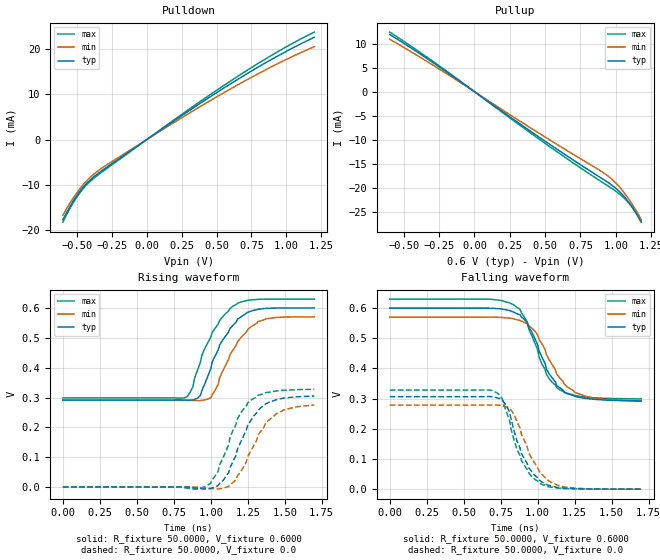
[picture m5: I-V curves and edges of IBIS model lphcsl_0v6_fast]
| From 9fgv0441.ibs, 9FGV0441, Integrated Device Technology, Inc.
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|   Model Clkout lphcsl_0v6_fast
[Model]  lphcsl_0v6_fast
Model_type Output
Polarity   Non-Inverting
Enable   Active-High
Vmeas =  0.4000V
Cref =   2.0000pF
Rref =   0.0
Vref =   0.4000V
C_comp   1.1000pF   1.0000pF   1.2000pF
[Temperature Range]   25.0000   75.0000   0.0
[Voltage Range]   0.6000V   0.5700V   0.6300V
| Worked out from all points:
|   slope of the pulldown table from 0 to 0.09 V, typ, clamps not added: 46.7 ohm
|   slope of the pullup table from 0 to 0.09 V, typ, clamps not added: 47.4 ohm
|   rising waveform, R_fixture 50.0000, V_fixture 0.6000: 20-80 % time 178ps typ, 179ps min, 178ps max; typ from 0.292 V to 0.6 V
|   rising waveform, R_fixture 50.0000, V_fixture 0.0: 20-80 % time 173ps typ, 176ps min, 168ps max; typ from 0 V to 0.305 V
|   falling waveform, R_fixture 50.0000, V_fixture 0.6000: 20-80 % time 182ps typ, 186ps min, 161ps max; typ from 0.6 V to 0.293 V
|   falling waveform, R_fixture 50.0000, V_fixture 0.0: 20-80 % time 140ps typ, 156ps min, 145ps max; typ from 0.306 V to 0 V
[Pulldown]
|Voltage   I(typ)   I(min)   I(max)
-600mV    -17.73mA   -16.75mA   -18.28mA
-540mV    -14.34mA   -13.62mA   -14.73mA
-480mV    -11.53mA   -10.95mA   -11.85mA
-440mV    -10.02mA   -9.465mA   -10.34mA
-400mV    -8.789mA   -8.218mA   -9.125mA
-320mV    -6.852mA   -6.295mA   -7.17mA
220mV     4.677mA    4.26mA     4.908mA
600mV     12.35mA    11.23mA    12.98mA
900mV     17.87mA    16.23mA    18.79mA
1.2V      22.67mA    20.58mA    23.82mA
[Pullup]
|Voltage   I(typ)   I(min)   I(max)
-600mV    11.94mA    10.94mA    12.43mA
-240mV    4.975mA    4.548mA    5.191mA
540mV     -11.13mA   -10.19mA   -11.61mA
940mV     -18.82mA   -17.47mA   -19.56mA
1V        -20.13mA   -19.02mA   -20.75mA
1.06V     -21.88mA   -21.09mA   -22.2mA
1.12V     -24.25mA   -23.65mA   -24.21mA
1.18V     -27.21mA   -26.66mA   -26.93mA
[Ramp]
| variable   typ   min   max
dV/dt_r  0.1828/0.1658n   0.1646/0.1750n   0.1965/0.1629n
dV/dt_f  0.1844/0.1738n   0.1666/0.1919n   0.1984/0.1620n
R_load = 50.0000
[Rising Waveform]
R_fixture= 50.0000
V_fixture= 0.6000
V_fixture_min= 0.5700
V_fixture_max= 0.6300
|time   V(typ)   V(min)   V(max)
0s        291.6mV    290.4mV    298.7mV
820ps     291.4mV    290.4mV    298.7mV
880ps     291.7mV    290.1mV    337.4mV
930ps     306.8mV    289.8mV    418.2mV
1ns       396.3mV    299.1mV    502.5mV
1.06ns    476mV      366.2mV    558.4mV
1.15ns    541.9mV    459.2mV    606.7mV
1.25ns    586mV      528.5mV    626.2mV
1.32ns    596mV      554.5mV    629.5mV
1.7ns     600.2mV    570.4mV    630.1mV
[Rising Waveform]
R_fixture= 50.0000
V_fixture= 0.0
V_fixture_min= 0.0
V_fixture_max= 0.0
|time   V(typ)   V(min)   V(max)
0s        0V         0V         0V
890ps     -3.58mV    -655.8uV   -7.526mV
1ns       -5.691mV   -4.788mV   12.59mV
1.05ns    4.772mV    -6.81mV    52.76mV
1.12ns    47.29mV    1.279mV    141.1mV
1.18ns    126.3mV    36.85mV    227.6mV
1.25ns    206.6mV    101.7mV    281.9mV
1.37ns    278.3mV    213.9mV    316.1mV
1.44ns    292.4mV    244.9mV    321.9mV
1.7ns     304.7mV    274.4mV    327.5mV
[Falling Waveform]
R_fixture= 50.0000
V_fixture= 0.6000
V_fixture_min= 0.5700
V_fixture_max= 0.6300
|time   V(typ)   V(min)   V(max)
0s        600mV      570mV      630mV
810ps     592.3mV    567mV      617.6mV
880ps     578.2mV    559.4mV    596.6mV
930ps     551.6mV    548.4mV    553.8mV
980ps     500.6mV    524.8mV    485.7mV
1.06ns    397.8mV    445.5mV    380.9mV
1.13ns    343.1mV    381.2mV    336.2mV
1.2ns     318mV      338.8mV    316.5mV
1.32ns    301.1mV    308.3mV    305.4mV
1.7ns     292.6mV    292.3mV    299.3mV
[Falling Waveform]
R_fixture= 50.0000
V_fixture= 0.0
V_fixture_min= 0.0
V_fixture_max= 0.0
|time   V(typ)   V(min)   V(max)
0s        306.5mV    278.5mV    328.5mV
690ps     306.6mV    278.8mV    327.3mV
760ps     296.2mV    277.1mV    300.6mV
810ps     256.1mV    268.7mV    227.7mV
820ps     233.2mV    262.8mV    199.6mV
890ps     118.8mV    182.7mV    95.62mV
1.01ns    30.83mV    59.83mV    20.86mV
1.06ns    15.44mV    32.63mV    10.17mV
1.18ns    3.389mV    7.484mV    2.238mV
1.7ns     139.5uV    252uV      103.6uV
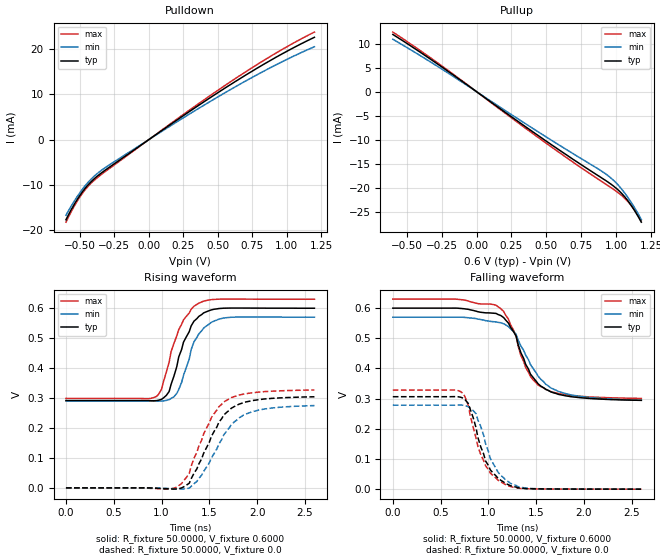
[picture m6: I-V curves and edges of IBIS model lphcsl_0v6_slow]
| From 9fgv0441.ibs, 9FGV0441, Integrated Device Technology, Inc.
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|   Model lphcsl_0v6_slow
[Model]  lphcsl_0v6_slow
Model_type Output
Polarity   Non-Inverting
Enable   Active-High
Vmeas =  0.4000V
Cref =   2.0000pF
Rref =   0.0
Vref =   0.4000V
C_comp   1.1000pF   1.0000pF   1.2000pF
[Temperature Range]   25.0000   75.0000   0.0
[Voltage Range]   0.6000V   0.5700V   0.6300V
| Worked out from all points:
|   slope of the pulldown table from 0 to 0.09 V, typ, clamps not added: 46.7 ohm
|   slope of the pullup table from 0 to 0.09 V, typ, clamps not added: 47.4 ohm
|   rising waveform, R_fixture 50.0000, V_fixture 0.6000: 20-80 % time 199ps typ, 187ps min, 207ps max; typ from 0.292 V to 0.6 V
|   rising waveform, R_fixture 50.0000, V_fixture 0.0: 20-80 % time 287ps typ, 320ps min, 278ps max; typ from 0 V to 0.304 V
|   falling waveform, R_fixture 50.0000, V_fixture 0.6000: 20-80 % time 277ps typ, 310ps min, 249ps max; typ from 0.6 V to 0.294 V
|   falling waveform, R_fixture 50.0000, V_fixture 0.0: 20-80 % time 196ps typ, 203ps min, 199ps max; typ from 0.306 V to 0 V
[Pulldown]
|Voltage   I(typ)   I(min)   I(max)
-600mV    -17.73mA   -16.75mA   -18.28mA
-540mV    -14.34mA   -13.62mA   -14.73mA
-480mV    -11.53mA   -10.95mA   -11.85mA
-440mV    -10.02mA   -9.465mA   -10.34mA
-400mV    -8.789mA   -8.218mA   -9.125mA
-320mV    -6.852mA   -6.295mA   -7.17mA
220mV     4.677mA    4.26mA     4.908mA
600mV     12.35mA    11.23mA    12.98mA
900mV     17.87mA    16.23mA    18.79mA
1.2V      22.67mA    20.58mA    23.82mA
[Pullup]
|Voltage   I(typ)   I(min)   I(max)
-600mV    11.94mA    10.94mA    12.43mA
-240mV    4.975mA    4.548mA    5.191mA
540mV     -11.13mA   -10.19mA   -11.61mA
940mV     -18.82mA   -17.47mA   -19.56mA
1V        -20.13mA   -19.02mA   -20.75mA
1.06V     -21.88mA   -21.09mA   -22.2mA
1.12V     -24.25mA   -23.65mA   -24.21mA
1.18V     -27.21mA   -26.66mA   -26.93mA
[Ramp]
| variable   typ   min   max
dV/dt_r  0.1826/0.2924n   0.1649/0.3119n   0.1961/0.2863n
dV/dt_f  0.1834/0.2952n   0.1651/0.3356n   0.1975/0.2766n
R_load = 50.0000
[Rising Waveform]
R_fixture= 50.0000
V_fixture= 0.6000
V_fixture_min= 0.5700
V_fixture_max= 0.6300
|time   V(typ)   V(min)   V(max)
0s        291.6mV    290.4mV    298.7mV
950ps     291.5mV    290mV      306.1mV
1ns       295.8mV    289.9mV    329.4mV
1.08ns    322.2mV    294.9mV    420.6mV
1.16ns    405.4mV    315.9mV    508.1mV
1.23ns    486.8mV    376mV      561.2mV
1.31ns    541mV      461.9mV    596.7mV
1.44ns    584.4mV    533.5mV    623.7mV
1.68ns    600.4mV    568.5mV    630.7mV
2.6ns     600.1mV    570.2mV    630.1mV
[Rising Waveform]
R_fixture= 50.0000
V_fixture= 0.0
V_fixture_min= 0.0
V_fixture_max= 0.0
|time   V(typ)   V(min)   V(max)
0s        0V         0V         0V
1.16ns    -3.564mV   -2.85mV    2.387mV
1.29ns    15.53mV    -1.023mV   47.73mV
1.34ns    48.97mV    13.95mV    99.71mV
1.37ns    63.74mV    21.58mV    119mV
1.52ns    170.6mV    99.09mV    233.8mV
1.65ns    243mV      176.5mV    286.9mV
1.81ns    279.5mV    233.7mV    310mV
1.94ns    291.2mV    253.8mV    317.4mV
2.6ns     304.3mV    274.9mV    326.9mV
[Falling Waveform]
R_fixture= 50.0000
V_fixture= 0.6000
V_fixture_min= 0.5700
V_fixture_max= 0.6300
|time   V(typ)   V(min)   V(max)
0s        600mV      570mV      630mV
1.08ns    582.5mV    554.3mV    609.7mV
1.16ns    568.6mV    548.2mV    589mV
1.29ns    507.2mV    513.2mV    507.8mV
1.34ns    451.9mV    474.6mV    442.6mV
1.39ns    413.8mV    444.1mV    403.1mV
1.52ns    349.3mV    374.6mV    345.2mV
1.65ns    323mV      336.1mV    323.8mV
1.86ns    306.7mV    312.7mV    310.9mV
2.6ns     294.4mV    294.9mV    300.8mV
[Falling Waveform]
R_fixture= 50.0000
V_fixture= 0.0
V_fixture_min= 0.0
V_fixture_max= 0.0
|time   V(typ)   V(min)   V(max)
0s        306.5mV    278.5mV    328.5mV
740ps     301.4mV    278.3mV    316.4mV
790ps     283.8mV    273.5mV    277.5mV
870ps     204.4mV    250.2mV    169.9mV
970ps     93.57mV    151.3mV    78.02mV
1.02ns    63.97mV    102.1mV    53.95mV
1.1ns     36.32mV    56.87mV    29.84mV
1.21ns    14.87mV    24.69mV    11.18mV
1.44ns    1.542mV    2.554mV    1.221mV
2.6ns     153.2uV    211.3uV    128.1uV
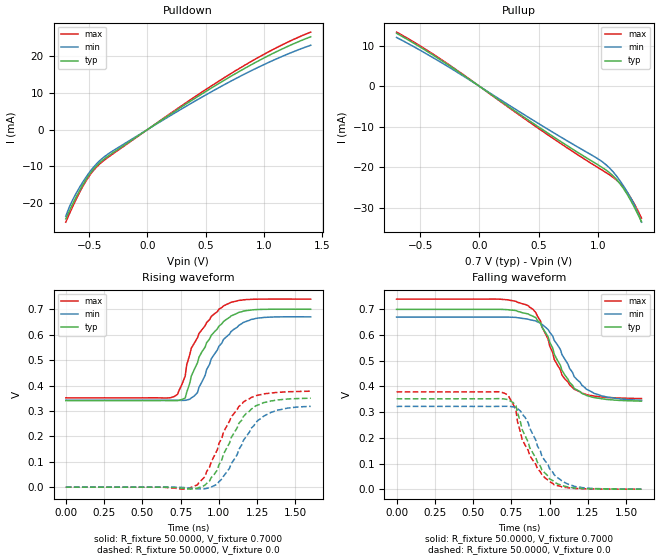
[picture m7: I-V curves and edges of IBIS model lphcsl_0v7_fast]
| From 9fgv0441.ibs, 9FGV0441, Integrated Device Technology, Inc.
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|   Model lphcsl_0v7_fast
[Model]  lphcsl_0v7_fast
Model_type Output
Polarity   Non-Inverting
Enable   Active-High
Vmeas =  0.4000V
Cref =   2.0000pF
Rref =   0.0
Vref =   0.4000V
C_comp   1.1000pF   1.0000pF   1.2000pF
[Temperature Range]   25.0000   75.0000   0.0
[Voltage Range]   0.7000V   0.6700V   0.7400V
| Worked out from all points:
|   slope of the pulldown table from 0 to 0.105 V, typ, clamps not added: 46.7 ohm
|   slope of the pullup table from 0 to 0.105 V, typ, clamps not added: 48.9 ohm
|   rising waveform, R_fixture 50.0000, V_fixture 0.7000: 20-80 % time 184ps typ, 189ps min, 167ps max; typ from 0.341 V to 0.7 V
|   rising waveform, R_fixture 50.0000, V_fixture 0.0: 20-80 % time 172ps typ, 185ps min, 179ps max; typ from 0 V to 0.35 V
|   falling waveform, R_fixture 50.0000, V_fixture 0.7000: 20-80 % time 180ps typ, 197ps min, 166ps max; typ from 0.7 V to 0.343 V
|   falling waveform, R_fixture 50.0000, V_fixture 0.0: 20-80 % time 157ps typ, 161ps min, 146ps max; typ from 0.352 V to 0 V
[Pulldown]
|Voltage   I(typ)   I(min)   I(max)
-700mV    -24.35mA   -23.64mA   -25.28mA
-670mV    -22.26mA   -21.16mA   -23.07mA
-640mV    -20.25mA   -19.13mA   -20.95mA
-580mV    -16.55mA   -15.66mA   -17.03mA
-520mV    -13.34mA   -12.68mA   -13.69mA
-430mV    -9.691mA   -9.131mA   -10.02mA
-340mV    -7.298mA   -6.726mA   -7.628mA
230mV     4.886mA    4.45mA     5.127mA
680mV     13.88mA    12.62mA    14.59mA
1.04V     20.22mA    18.36mA    21.25mA
1.22V     22.96mA    20.85mA    24.13mA
1.4V      25.34mA    23.03mA    26.62mA
[Pullup]
|Voltage   I(typ)   I(min)   I(max)
-700mV    13.05mA    12.03mA    13.35mA
-490mV    9.468mA    8.696mA    9.752mA
-310mV    6.146mA    5.633mA    6.355mA
500mV     -10.03mA   -9.194mA   -10.4mA
800mV     -15.73mA   -14.45mA   -16.3mA
1.04V     -20.06mA   -18.64mA   -20.72mA
1.13V     -22.08mA   -21.08mA   -22.44mA
1.22V     -25.3mA    -24.66mA   -24.97mA
1.25V     -26.68mA   -26.08mA   -26.14mA
1.31V     -29.84mA   -29.28mA   -29.02mA
1.34V     -31.57mA   -31.17mA   -30.68mA
1.37V     -33.4mA    -33.5mA    -32.47mA
[Ramp]
| variable   typ   min   max
dV/dt_r  0.2101/0.1771n   0.1909/0.1879n   0.2266/0.1755n
dV/dt_f  0.2143/0.1763n   0.1943/0.1928n   0.2323/0.1650n
R_load = 50.0000
[Rising Waveform]
R_fixture= 50.0000
V_fixture= 0.7000
V_fixture_min= 0.6700
V_fixture_max= 0.7400
|time   V(typ)   V(min)   V(max)
0s        340.9mV    342mV      351.5mV
710ps     340.3mV    342mV      357.1mV
780ps     350.7mV    341.7mV    436.8mV
790ps     373.5mV    343.1mV    481.7mV
820ps     437.2mV    351.1mV    546.8mV
860ps     489mV      371.9mV    587.6mV
950ps     597.2mV    505.1mV    671.9mV
1.03ns    651.8mV    581.1mV    713.2mV
1.21ns    697.1mV    659.9mV    739.1mV
1.6ns     700.1mV    670.3mV    740.1mV
[Rising Waveform]
R_fixture= 50.0000
V_fixture= 0.0
V_fixture_min= 0.0
V_fixture_max= 0.0
|time   V(typ)   V(min)   V(max)
0s        0V         0V         0V
810ps     -7.521mV   -3.728mV   -3.151mV
910ps     8.285mV    -6.321mV   42.33mV
990ps     67.83mV    11.68mV    147.1mV
1.03ns    130.4mV    42.94mV    216.4mV
1.08ns    194.2mV    91.72mV    275.7mV
1.16ns    277.7mV    184mV      335mV
1.24ns    320mV      253.8mV    360.2mV
1.31ns    334.7mV    285mV      368.4mV
1.6ns     350.1mV    318.1mV    377.6mV
[Falling Waveform]
R_fixture= 50.0000
V_fixture= 0.7000
V_fixture_min= 0.6700
V_fixture_max= 0.7400
|time   V(typ)   V(min)   V(max)
0s        700mV      670mV      740mV
680ps     700mV      670.1mV    739.5mV
840ps     684.7mV    663.5mV    719.1mV
910ps     667.5mV    654.9mV    687.2mV
990ps     593.6mV    621.5mV    584.4mV
1.03ns    525.9mV    579.3mV    505.2mV
1.08ns    463.2mV    524.7mV    445mV
1.16ns    392.3mV    438.1mV    389.5mV
1.29ns    356.6mV    373mV      362.4mV
1.6ns     342.9mV    346.1mV    352.9mV
[Falling Waveform]
R_fixture= 50.0000
V_fixture= 0.0
V_fixture_min= 0.0
V_fixture_max= 0.0
|time   V(typ)   V(min)   V(max)
0s        351.9mV    322.2mV    378.7mV
710ps     350.9mV    322.7mV    372.3mV
780ps     325.6mV    318.9mV    307.6mV
790ps     297.8mV    313.5mV    262.9mV
820ps     232.9mV    292.8mV    194.6mV
840ps     207.9mV    279.3mV    171.4mV
920ps     104.8mV    168.4mV    80.17mV
1ns       40.1mV     79.05mV    29.21mV
1.16ns    4.805mV    11.18mV    3.196mV
1.6ns     236.9uV    414.6uV    176.6uV
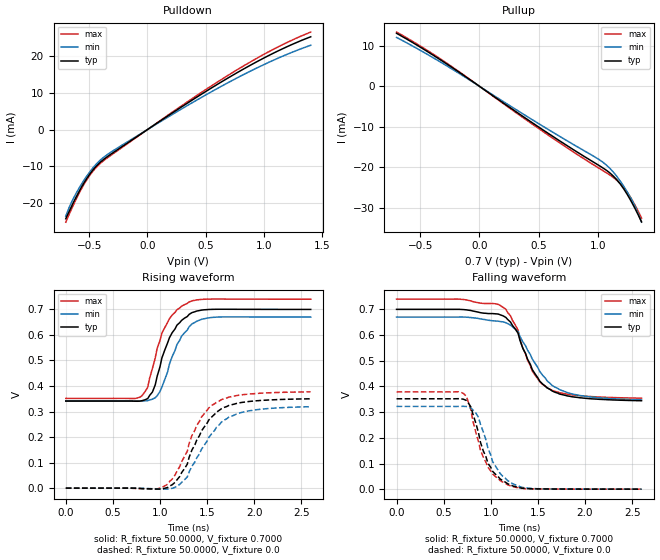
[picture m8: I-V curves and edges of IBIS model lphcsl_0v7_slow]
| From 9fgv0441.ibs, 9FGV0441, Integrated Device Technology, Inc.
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|   Model lphcsl_0v7_slow
[Model]  lphcsl_0v7_slow
Model_type Output
Polarity   Non-Inverting
Enable   Active-High
Vmeas =  0.4000V
Cref =   2.0000pF
Rref =   0.0
Vref =   0.4000V
C_comp   1.1000pF   1.0000pF   1.2000pF
[Temperature Range]   25.0000   75.0000   0.0
[Voltage Range]   0.7000V   0.6700V   0.7400V
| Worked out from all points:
|   slope of the pulldown table from 0 to 0.105 V, typ, clamps not added: 46.7 ohm
|   slope of the pullup table from 0 to 0.105 V, typ, clamps not added: 48.9 ohm
|   rising waveform, R_fixture 50.0000, V_fixture 0.7000: 20-80 % time 211ps typ, 219ps min, 209ps max; typ from 0.341 V to 0.7 V
|   rising waveform, R_fixture 50.0000, V_fixture 0.0: 20-80 % time 305ps typ, 334ps min, 298ps max; typ from 0 V to 0.35 V
|   falling waveform, R_fixture 50.0000, V_fixture 0.7000: 20-80 % time 285ps typ, 331ps min, 271ps max; typ from 0.7 V to 0.344 V
|   falling waveform, R_fixture 50.0000, V_fixture 0.0: 20-80 % time 198ps typ, 207ps min, 198ps max; typ from 0.352 V to 0 V
[Pulldown]
|Voltage   I(typ)   I(min)   I(max)
-700mV    -24.35mA   -23.64mA   -25.28mA
-670mV    -22.26mA   -21.16mA   -23.07mA
-640mV    -20.25mA   -19.13mA   -20.95mA
-580mV    -16.55mA   -15.66mA   -17.03mA
-520mV    -13.34mA   -12.68mA   -13.69mA
-430mV    -9.691mA   -9.131mA   -10.02mA
-340mV    -7.298mA   -6.726mA   -7.628mA
230mV     4.886mA    4.45mA     5.127mA
680mV     13.88mA    12.62mA    14.59mA
1.04V     20.22mA    18.36mA    21.25mA
1.22V     22.96mA    20.85mA    24.13mA
1.4V      25.34mA    23.03mA    26.62mA
[Pullup]
|Voltage   I(typ)   I(min)   I(max)
-700mV    13.05mA    12.03mA    13.35mA
-490mV    9.468mA    8.696mA    9.752mA
-310mV    6.146mA    5.633mA    6.355mA
500mV     -10.03mA   -9.194mA   -10.4mA
800mV     -15.73mA   -14.45mA   -16.3mA
1.04V     -20.06mA   -18.64mA   -20.72mA
1.13V     -22.08mA   -21.08mA   -22.44mA
1.22V     -25.3mA    -24.66mA   -24.97mA
1.25V     -26.68mA   -26.08mA   -26.14mA
1.31V     -29.84mA   -29.28mA   -29.02mA
1.34V     -31.57mA   -31.17mA   -30.68mA
1.37V     -33.4mA    -33.5mA    -32.47mA
[Ramp]
| variable   typ   min   max
dV/dt_r  0.2099/0.3249n   0.1913/0.3440n   0.2263/0.3187n
dV/dt_f  0.2134/0.3076n   0.1934/0.3467n   0.2314/0.2897n
R_load = 50.0000
[Rising Waveform]
R_fixture= 50.0000
V_fixture= 0.7000
V_fixture_min= 0.6700
V_fixture_max= 0.7400
|time   V(typ)   V(min)   V(max)
0s        340.9mV    342mV      351.5mV
790ps     340.9mV    341.6mV    356.5mV
870ps     350.8mV    342.8mV    395.1mV
920ps     376.5mV    348.5mV    469.3mV
1.02ns    509.7mV    395.5mV    607mV
1.1ns     589mV      485.4mV    663.5mV
1.18ns    638.4mV    562.8mV    698.5mV
1.31ns    680.9mV    632.5mV    729.3mV
1.55ns    700.2mV    668.6mV    740.6mV
2.6ns     700.1mV    670.1mV    740mV
[Rising Waveform]
R_fixture= 50.0000
V_fixture= 0.0
V_fixture_min= 0.0
V_fixture_max= 0.0
|time   V(typ)   V(min)   V(max)
0s        0V         0V         0V
1ns       -3.725mV   -2.933mV   -269.6uV
1.13ns    13.32mV    -760.9uV   35.8mV
1.29ns    94.06mV    44.03mV    144.8mV
1.34ns    150.1mV    86.22mV    207mV
1.44ns    223.7mV    151.8mV    278.4mV
1.6ns     297.4mV    238.6mV    336.3mV
1.73ns    323.7mV    277.7mV    356.2mV
1.89ns    336.7mV    298.6mV    366.5mV
2.6ns     349.9mV    318.9mV    377.2mV
[Falling Waveform]
R_fixture= 50.0000
V_fixture= 0.7000
V_fixture_min= 0.6700
V_fixture_max= 0.7400
|time   V(typ)   V(min)   V(max)
0s        700mV      670mV      740mV
660ps     700.1mV    670mV      740mV
1.08ns    681.7mV    654mV      719mV
1.16ns    668.7mV    648.1mV    700.4mV
1.29ns    606.7mV    613mV      618.6mV
1.34ns    549.2mV    573.8mV    549mV
1.44ns    466.1mV    507mV      460.6mV
1.6ns     394.2mV    421mV      394.1mV
1.94ns    356.1mV    365mV      364.1mV
2.6ns     344.4mV    347.6mV    354.3mV
[Falling Waveform]
R_fixture= 50.0000
V_fixture= 0.0
V_fixture_min= 0.0
V_fixture_max= 0.0
|time   V(typ)   V(min)   V(max)
0s        351.9mV    322.2mV    378.7mV
710ps     350.2mV    322.6mV    372.8mV
740ps     345.7mV    322mV      362.4mV
790ps     319.4mV    315.9mV    307.2mV
870ps     219.5mV    279.9mV    184.3mV
970ps     100.9mV    159.3mV    85.56mV
1.02ns    69.37mV    107.3mV    59.48mV
1.18ns    21.11mV    33.12mV    17.12mV
1.44ns    1.65mV     2.75mV     1.363mV
2.6ns     158uV      217uV      133.3uV
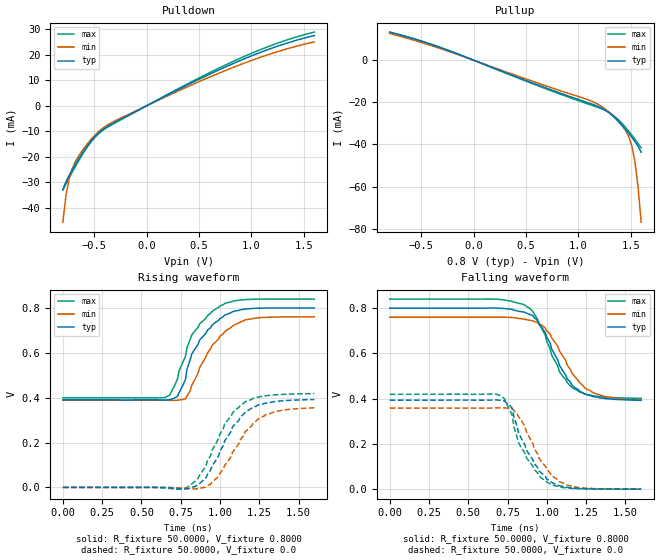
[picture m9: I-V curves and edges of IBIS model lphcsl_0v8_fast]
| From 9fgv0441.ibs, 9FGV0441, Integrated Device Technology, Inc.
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|   Model lphcsl_0v8_fast
[Model]  lphcsl_0v8_fast
Model_type Output
Polarity   Non-Inverting
Enable   Active-High
Vmeas =  0.4000V
Cref =   2.0000pF
Rref =   0.0
Vref =   0.4000V
C_comp   1.1000pF   1.0000pF   1.2000pF
[Temperature Range]   25.0000   75.0000   0.0
[Voltage Range]   0.8000V   0.7600V   0.8400V
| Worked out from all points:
|   slope of the pulldown table from 0 to 0.12 V, typ, clamps not added: 46.7 ohm
|   slope of the pullup table from 0 to 0.12 V, typ, clamps not added: 51 ohm
|   rising waveform, R_fixture 50.0000, V_fixture 0.8000: 20-80 % time 171ps typ, 195ps min, 176ps max; typ from 0.39 V to 0.8 V
|   rising waveform, R_fixture 50.0000, V_fixture 0.0: 20-80 % time 189ps typ, 199ps min, 184ps max; typ from 0 V to 0.392 V
|   falling waveform, R_fixture 50.0000, V_fixture 0.8000: 20-80 % time 185ps typ, 195ps min, 175ps max; typ from 0.8 V to 0.393 V
|   falling waveform, R_fixture 50.0000, V_fixture 0.0: 20-80 % time 160ps typ, 168ps min, 150ps max; typ from 0.394 V to 0 V
[Pulldown]
|Voltage   I(typ)   I(min)   I(max)
-800mV    -32.9mA    -45.7mA    -33.08mA
-770mV    -29.78mA   -35.16mA   -30.65mA
-740mV    -27.3mA    -28.65mA   -28.32mA
-710mV    -25.06mA   -24.65mA   -26.03mA
-650mV    -20.91mA   -19.77mA   -21.65mA
-590mV    -17.13mA   -16.2mA    -17.65mA
-500mV    -12.4mA    -11.79mA   -12.73mA
-410mV    -9.074mA   -8.508mA   -9.407mA
190mV     4.047mA    3.687mA    4.247mA
790mV     15.92mA    14.46mA    16.73mA
1.21V     22.81mA    20.72mA    23.98mA
1.6V      27.55mA    25.07mA    28.91mA
[Pullup]
|Voltage   I(typ)   I(min)   I(max)
-800mV    13.33mA    12.66mA    13.23mA
-290mV    5.458mA    5.059mA    5.585mA
580mV     -11.13mA   -10.28mA   -11.48mA
1.09V     -20.16mA   -18.75mA   -20.77mA
1.24V     -23.23mA   -22.57mA   -23.45mA
1.33V     -26.53mA   -26.31mA   -26.04mA
1.42V     -31.1mA    -31.15mA   -30.17mA
1.48V     -34.66mA   -36.14mA   -33.64mA
1.51V     -36.57mA   -40.62mA   -35.53mA
1.54V     -38.58mA   -48.09mA   -37.5mA
1.57V     -40.83mA   -60mA      -39.53mA
1.6V      -43.71mA   -76.91mA   -41.59mA
[Ramp]
| variable   typ   min   max
dV/dt_r  0.2351/0.1904n   0.2130/0.1984n   0.2511/0.1876n
dV/dt_f  0.2443/0.1800n   0.2199/0.1961n   0.2631/0.1717n
R_load = 50.0000
[Rising Waveform]
R_fixture= 50.0000
V_fixture= 0.8000
V_fixture_min= 0.7600
V_fixture_max= 0.8400
|time   V(typ)   V(min)   V(max)
0s        390.4mV    388.7mV    399.8mV
650ps     389.8mV    388.7mV    401.3mV
680ps     391.1mV    388.4mV    411.6mV
730ps     407.3mV    388.7mV    485.3mV
780ps     481mV      395.2mV    584.4mV
820ps     594.6mV    455.3mV    679.7mV
870ps     656.9mV    534.1mV    729.2mV
1ns       752.9mV    674.1mV    809mV
1.16ns    795.5mV    746.9mV    837.8mV
1.6ns     800.1mV    760.2mV    840mV
[Rising Waveform]
R_fixture= 50.0000
V_fixture= 0.0
V_fixture_min= 0.0
V_fixture_max= 0.0
|time   V(typ)   V(min)   V(max)
0s        0V         0V         0V
780ps     -7.46mV    -3.895mV   -4.263mV
860ps     10.6mV     -6.078mV   40.37mV
940ps     77.21mV    14.66mV    141.6mV
990ps     139.4mV    48.05mV    216.6mV
1.03ns    207.8mV    98.38mV    283mV
1.16ns    334.9mV    248.1mV    381.9mV
1.24ns    367.3mV    303.3mV    402.4mV
1.34ns    381.9mV    335.5mV    412.4mV
1.6ns     391.9mV    355mV      418.5mV
[Falling Waveform]
R_fixture= 50.0000
V_fixture= 0.8000
V_fixture_min= 0.7600
V_fixture_max= 0.8400
|time   V(typ)   V(min)   V(max)
0s        800mV      760mV      840mV
680ps     800.1mV    760.1mV    839.5mV
840ps     784.1mV    752.6mV    818.7mV
910ps     767.1mV    743.9mV    786.4mV
990ps     691.6mV    711.5mV    680.2mV
1.08ns    547.5mV    611.1mV    518.8mV
1.16ns    459.8mV    512.1mV    448.9mV
1.24ns    420.9mV    447.8mV    420.9mV
1.31ns    407.5mV    422.2mV    411.3mV
1.6ns     392.9mV    393.5mV    401.5mV
[Falling Waveform]
R_fixture= 50.0000
V_fixture= 0.0
V_fixture_min= 0.0
V_fixture_max= 0.0
|time   V(typ)   V(min)   V(max)
0s        393.5mV    358.7mV    419.5mV
680ps     394.5mV    359mV      419.6mV
730ps     389.5mV    359.4mV    400mV
780ps     357.4mV    354.8mV    325.5mV
790ps     321.4mV    347.7mV    276.6mV
810ps     278mV      334.4mV    230.2mV
870ps     172mV      252.6mV    139mV
1ns       44.35mV    86.95mV    31.69mV
1.16ns    5.274mV    12.46mV    3.44mV
1.6ns     247.6uV    416.9uV    181.2uV
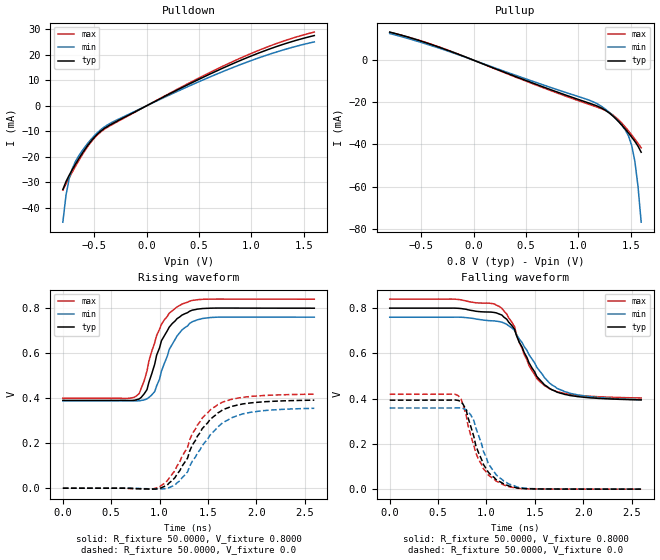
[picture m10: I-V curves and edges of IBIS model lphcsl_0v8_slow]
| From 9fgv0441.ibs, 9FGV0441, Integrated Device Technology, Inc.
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|   Model lphcsl_0v8_slow
[Model]  lphcsl_0v8_slow
Model_type Output
Polarity   Non-Inverting
Enable   Active-High
Vmeas =  0.4000V
Cref =   2.0000pF
Rref =   0.0
Vref =   0.4000V
C_comp   1.1000pF   1.0000pF   1.2000pF
[Temperature Range]   25.0000   75.0000   0.0
[Voltage Range]   0.8000V   0.7600V   0.8400V
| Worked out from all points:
|   slope of the pulldown table from 0 to 0.12 V, typ, clamps not added: 46.7 ohm
|   slope of the pullup table from 0 to 0.12 V, typ, clamps not added: 51 ohm
|   rising waveform, R_fixture 50.0000, V_fixture 0.8000: 20-80 % time 213ps typ, 221ps min, 209ps max; typ from 0.39 V to 0.8 V
|   rising waveform, R_fixture 50.0000, V_fixture 0.0: 20-80 % time 334ps typ, 348ps min, 330ps max; typ from 0 V to 0.391 V
|   falling waveform, R_fixture 50.0000, V_fixture 0.8000: 20-80 % time 300ps typ, 348ps min, 281ps max; typ from 0.8 V to 0.395 V
|   falling waveform, R_fixture 50.0000, V_fixture 0.0: 20-80 % time 203ps typ, 207ps min, 197ps max; typ from 0.394 V to 0 V
[Pulldown]
|Voltage   I(typ)   I(min)   I(max)
-800mV    -32.9mA    -45.7mA    -33.08mA
-770mV    -29.78mA   -35.16mA   -30.65mA
-740mV    -27.3mA    -28.65mA   -28.32mA
-710mV    -25.06mA   -24.65mA   -26.03mA
-650mV    -20.91mA   -19.77mA   -21.65mA
-590mV    -17.13mA   -16.2mA    -17.65mA
-500mV    -12.4mA    -11.79mA   -12.73mA
-410mV    -9.074mA   -8.508mA   -9.407mA
190mV     4.047mA    3.687mA    4.247mA
790mV     15.92mA    14.46mA    16.73mA
1.21V     22.81mA    20.72mA    23.98mA
1.6V      27.55mA    25.07mA    28.91mA
[Pullup]
|Voltage   I(typ)   I(min)   I(max)
-800mV    13.33mA    12.66mA    13.23mA
-290mV    5.458mA    5.059mA    5.585mA
580mV     -11.13mA   -10.28mA   -11.48mA
1.09V     -20.16mA   -18.75mA   -20.77mA
1.24V     -23.23mA   -22.57mA   -23.45mA
1.33V     -26.53mA   -26.31mA   -26.04mA
1.42V     -31.1mA    -31.15mA   -30.17mA
1.48V     -34.66mA   -36.14mA   -33.64mA
1.51V     -36.57mA   -40.62mA   -35.53mA
1.54V     -38.58mA   -48.09mA   -37.5mA
1.57V     -40.83mA   -60mA      -39.53mA
1.6V      -43.71mA   -76.91mA   -41.59mA
[Ramp]
| variable   typ   min   max
dV/dt_r  0.2348/0.3588n   0.2131/0.3733n   0.2507/0.3535n
dV/dt_f  0.2432/0.3203n   0.2188/0.3592n   0.2621/0.3037n
R_load = 50.0000
[Rising Waveform]
R_fixture= 50.0000
V_fixture= 0.8000
V_fixture_min= 0.7600
V_fixture_max= 0.8400
|time   V(typ)   V(min)   V(max)
0s        390.4mV    388.7mV    399.8mV
760ps     393.2mV    388.1mV    409.9mV
790ps     396.7mV    388.6mV    421.1mV
870ps     438mV      397.2mV    520.8mV
950ps     551.4mV    429.8mV    647.1mV
1.02ns    655.9mV    520.9mV    728.7mV
1.1ns     715.9mV    616.7mV    778mV
1.23ns    768.9mV    702.6mV    817.7mV
1.52ns    800mV      758.4mV    840.3mV
2.6ns     800mV      760.1mV    840mV
[Rising Waveform]
R_fixture= 50.0000
V_fixture= 0.0
V_fixture_min= 0.0
V_fixture_max= 0.0
|time   V(typ)   V(min)   V(max)
0s        0V         0V         0V
1ns       -406.6uV   -3.37mV    6.406mV
1.08ns    14.06mV    82.67uV    33.18mV
1.21ns    78.46mV    33.07mV    118.4mV
1.29ns    134.3mV    72.92mV    182.2mV
1.39ns    230.5mV    155.1mV    279.7mV
1.6ns     333.9mV    271.7mV    371.5mV
1.73ns    361.6mV    310.3mV    393.6mV
1.94ns    379.1mV    337.3mV    407.9mV
2.6ns     391.3mV    355.1mV    417.9mV
[Falling Waveform]
R_fixture= 50.0000
V_fixture= 0.8000
V_fixture_min= 0.7600
V_fixture_max= 0.8400
|time   V(typ)   V(min)   V(max)
0s        800mV      760mV      840mV
1.08ns    780.9mV    743.6mV    818.9mV
1.16ns    769.4mV    737.9mV    798.8mV
1.29ns    707.6mV    702.6mV    718.4mV
1.34ns    648.7mV    663.1mV    647.6mV
1.44ns    558.7mV    594.3mV    546mV
1.6ns     461.3mV    492.9mV    457.7mV
1.73ns    428.8mV    445.6mV    430.6mV
1.86ns    414.2mV    424.2mV    419.2mV
2.6ns     394.6mV    395.4mV    403.1mV
[Falling Waveform]
R_fixture= 50.0000
V_fixture= 0.0
V_fixture_min= 0.0
V_fixture_max= 0.0
|time   V(typ)   V(min)   V(max)
0s        393.5mV    358.7mV    419.5mV
710ps     392mV      359.3mV    412.7mV
740ps     386.1mV    358.9mV    396.6mV
790ps     350.8mV    351.5mV    327.8mV
870ps     232.4mV    302.7mV    192.3mV
920ps     159.4mV    235.9mV    130.6mV
1.02ns    74.65mV    112.1mV    62.15mV
1.18ns    23.12mV    35.37mV    18.49mV
1.44ns    1.783mV    3.078mV    1.353mV
2.6ns     162.7uV    222.5uV    136.9uV
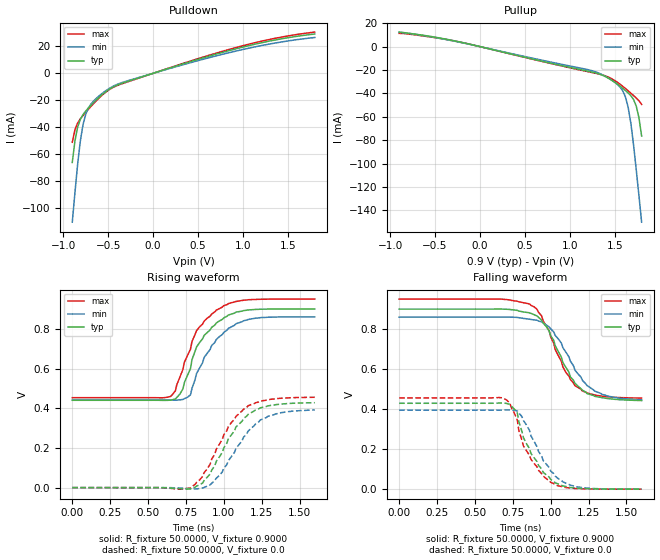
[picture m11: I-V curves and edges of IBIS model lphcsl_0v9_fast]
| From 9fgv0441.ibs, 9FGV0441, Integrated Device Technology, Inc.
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|   Model lphcsl_0v9_fast
[Model]  lphcsl_0v9_fast
Model_type Output
Polarity   Non-Inverting
Enable   Active-High
Vmeas =  0.4000V
Cref =   2.0000pF
Rref =   0.0
Vref =   0.4000V
C_comp   1.1000pF   1.0000pF   1.2000pF
[Temperature Range]   25.0000   75.0000   0.0
[Voltage Range]   0.9000V   0.8600V   0.9500V
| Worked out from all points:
|   slope of the pulldown table from 0 to 0.135 V, typ, clamps not added: 46.8 ohm
|   slope of the pullup table from 0 to 0.135 V, typ, clamps not added: 54.2 ohm
|   rising waveform, R_fixture 50.0000, V_fixture 0.9000: 20-80 % time 179ps typ, 193ps min, 178ps max; typ from 0.44 V to 0.9 V
|   rising waveform, R_fixture 50.0000, V_fixture 0.0: 20-80 % time 207ps typ, 212ps min, 201ps max; typ from 0 V to 0.428 V
|   falling waveform, R_fixture 50.0000, V_fixture 0.9000: 20-80 % time 182ps typ, 203ps min, 180ps max; typ from 0.9 V to 0.443 V
|   falling waveform, R_fixture 50.0000, V_fixture 0.0: 20-80 % time 161ps typ, 174ps min, 155ps max; typ from 0.43 V to 0 V
[Pulldown]
|Voltage   I(typ)   I(min)   I(max)
-900mV    -66.41mA   -110.9mA   -51.33mA
-870mV    -50.28mA   -88.64mA   -42.02mA
-840mV    -40.04mA   -67.5mA    -37.02mA
-810mV    -34.24mA   -50.31mA   -33.94mA
-780mV    -30.72mA   -38.16mA   -31.45mA
-750mV    -28.09mA   -30.47mA   -29.09mA
-720mV    -25.79mA   -25.8mA    -26.79mA
-570mV    -15.97mA   -15.13mA   -16.43mA
-330mV    -7.073mA   -6.508mA   -7.398mA
660mV     13.5mA     12.27mA    14.19mA
1.26V     23.52mA    21.36mA    24.72mA
1.8V      29.29mA    26.69mA    30.72mA
[Pullup]
|Voltage   I(typ)   I(min)   I(max)
-900mV    12.42mA    12.23mA    11.33mA
-240mV    4.199mA    3.949mA    4.146mA
1.2V      -21.02mA   -19.69mA   -21.4mA
1.35V     -24.09mA   -23.58mA   -23.95mA
1.5V      -30.44mA   -30.47mA   -29.02mA
1.59V     -35.67mA   -37.86mA   -33.98mA
1.62V     -37.59mA   -43.14mA   -35.86mA
1.65V     -39.64mA   -51.94mA   -37.81mA
1.68V     -42.02mA   -65.49mA   -39.82mA
1.74V     -50.81mA   -105.3mA   -43.98mA
1.77V     -60.74mA   -127.4mA   -46.3mA
1.8V      -76.52mA   -150.2mA   -49.53mA
[Ramp]
| variable   typ   min   max
dV/dt_r  0.2567/0.2031n   0.2348/0.2108n   0.2732/0.2011n
dV/dt_f  0.2742/0.1835n   0.2479/0.1986n   0.2969/0.1767n
R_load = 50.0000
[Rising Waveform]
R_fixture= 50.0000
V_fixture= 0.9000
V_fixture_min= 0.8600
V_fixture_max= 0.9500
|time   V(typ)   V(min)   V(max)
0s        440.1mV    440.9mV    453.2mV
650ps     440.7mV    440.5mV    460.2mV
680ps     446.5mV    440.4mV    487.3mV
710ps     471.2mV    442.3mV    556.7mV
780ps     599.4mV    467.4mV    697.4mV
790ps     645.2mV    500.2mV    736.4mV
820ps     708.7mV    574.5mV    791.1mV
950ps     829mV      745.9mV    894.2mV
1.16ns    895mV      847.1mV    946.6mV
1.6ns     900.1mV    860.2mV    950mV
[Rising Waveform]
R_fixture= 50.0000
V_fixture= 0.0
V_fixture_min= 0.0
V_fixture_max= 0.0
|time   V(typ)   V(min)   V(max)
0s        0V         0V         0V
780ps     -6.289mV   -5.183mV   -1.707mV
860ps     23.22mV    -1.704mV   56.79mV
940ps     109.8mV    34.62mV    168.3mV
1.03ns    245.9mV    135.9mV    307.6mV
1.08ns    305.5mV    197.6mV    358.5mV
1.16ns    368.6mV    284.2mV    412.4mV
1.24ns    401.8mV    340.4mV    435.5mV
1.31ns    414.4mV    363.9mV    445.1mV
1.6ns     427.9mV    391.3mV    455.3mV
[Falling Waveform]
R_fixture= 50.0000
V_fixture= 0.9000
V_fixture_min= 0.8600
V_fixture_max= 0.9500
|time   V(typ)   V(min)   V(max)
0s        900mV      860mV      950mV
680ps     900.1mV    860.1mV    949.6mV
860ps     881.3mV    849.9mV    925.6mV
940ps     845.1mV    836.2mV    866.5mV
1.02ns    743.6mV    786mV      729.4mV
1.08ns    633.1mV    707.7mV    611.8mV
1.16ns    529.7mV    594.9mV    517.5mV
1.24ns    478mV      517.9mV    481.1mV
1.34ns    457.1mV    473.4mV    464.6mV
1.6ns     443mV      446.8mV    455.2mV
[Falling Waveform]
R_fixture= 50.0000
V_fixture= 0.0
V_fixture_min= 0.0
V_fixture_max= 0.0
|time   V(typ)   V(min)   V(max)
0s        429.5mV    395.1mV    456.2mV
680ps     431mV      395.4mV    456.7mV
730ps     424mV      396.2mV    430.6mV
780ps     380.4mV    391.1mV    345mV
790ps     336.6mV    381.2mV    292.6mV
810ps     288.7mV    362.9mV    245.3mV
870ps     178.5mV    266.6mV    149.2mV
1ns       48.68mV    90.54mV    34.39mV
1.16ns    5.71mV     12.72mV    3.587mV
1.6ns     250.5uV    436.1uV    182.5uV
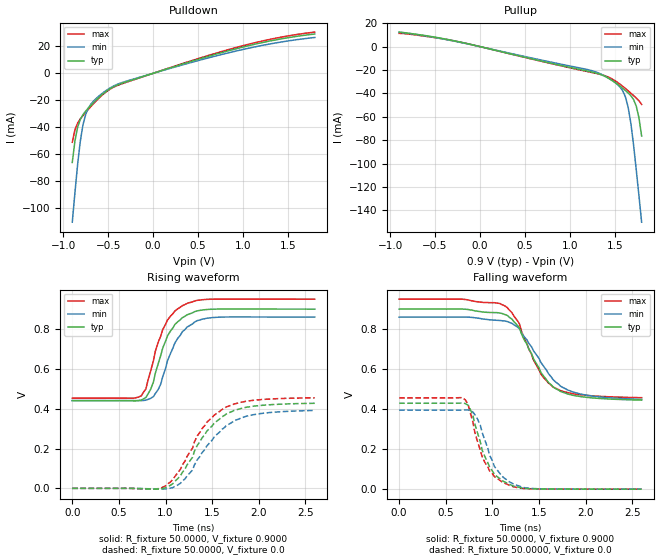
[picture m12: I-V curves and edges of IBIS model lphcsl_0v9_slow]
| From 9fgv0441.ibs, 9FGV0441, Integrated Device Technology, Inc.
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|   Model lphcsl_0v9_slow
[Model]  lphcsl_0v9_slow
Model_type Output
Polarity   Non-Inverting
Enable   Active-High
Vmeas =  0.4000V
Cref =   2.0000pF
Rref =   0.0
Vref =   0.4000V
C_comp   1.1000pF   1.0000pF   1.2000pF
[Temperature Range]   25.0000   75.0000   0.0
[Voltage Range]   0.9000V   0.8600V   0.9500V
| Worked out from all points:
|   slope of the pulldown table from 0 to 0.135 V, typ, clamps not added: 46.8 ohm
|   slope of the pullup table from 0 to 0.135 V, typ, clamps not added: 54.2 ohm
|   rising waveform, R_fixture 50.0000, V_fixture 0.9000: 20-80 % time 213ps typ, 218ps min, 212ps max; typ from 0.44 V to 0.9 V
|   rising waveform, R_fixture 50.0000, V_fixture 0.0: 20-80 % time 373ps typ, 385ps min, 363ps max; typ from 0 V to 0.427 V
|   falling waveform, R_fixture 50.0000, V_fixture 0.9000: 20-80 % time 311ps typ, 372ps min, 299ps max; typ from 0.9 V to 0.445 V
|   falling waveform, R_fixture 50.0000, V_fixture 0.0: 20-80 % time 204ps typ, 207ps min, 197ps max; typ from 0.43 V to 0 V
[Pulldown]
|Voltage   I(typ)   I(min)   I(max)
-900mV    -66.41mA   -110.9mA   -51.33mA
-870mV    -50.28mA   -88.64mA   -42.02mA
-840mV    -40.04mA   -67.5mA    -37.02mA
-810mV    -34.24mA   -50.31mA   -33.94mA
-780mV    -30.72mA   -38.16mA   -31.45mA
-750mV    -28.09mA   -30.47mA   -29.09mA
-720mV    -25.79mA   -25.8mA    -26.79mA
-570mV    -15.97mA   -15.13mA   -16.43mA
-330mV    -7.073mA   -6.508mA   -7.398mA
660mV     13.5mA     12.27mA    14.19mA
1.26V     23.52mA    21.36mA    24.72mA
1.8V      29.29mA    26.69mA    30.72mA
[Pullup]
|Voltage   I(typ)   I(min)   I(max)
-900mV    12.42mA    12.23mA    11.33mA
-240mV    4.199mA    3.949mA    4.146mA
1.2V      -21.02mA   -19.69mA   -21.4mA
1.35V     -24.09mA   -23.58mA   -23.95mA
1.5V      -30.44mA   -30.47mA   -29.02mA
1.59V     -35.67mA   -37.86mA   -33.98mA
1.62V     -37.59mA   -43.14mA   -35.86mA
1.65V     -39.64mA   -51.94mA   -37.81mA
1.68V     -42.02mA   -65.49mA   -39.82mA
1.74V     -50.81mA   -105.3mA   -43.98mA
1.77V     -60.74mA   -127.4mA   -46.3mA
1.8V      -76.52mA   -150.2mA   -49.53mA
[Ramp]
| variable   typ   min   max
dV/dt_r  0.2563/0.3926n   0.2347/0.4108n   0.2727/0.3901n
dV/dt_f  0.2729/0.3367n   0.2467/0.3752n   0.2957/0.3199n
R_load = 50.0000
[Rising Waveform]
R_fixture= 50.0000
V_fixture= 0.9000
V_fixture_min= 0.8600
V_fixture_max= 0.9500
|time   V(typ)   V(min)   V(max)
0s        440.1mV    440.9mV    453.2mV
740ps     443.4mV    440.3mV    464.7mV
790ps     456.4mV    442.8mV    499.7mV
840ps     496.8mV    451.9mV    588.4mV
920ps     623.7mV    494.9mV    732mV
970ps     704.6mV    561.2mV    797.7mV
1.1ns     822.7mV    729.7mV    890.7mV
1.23ns    871.3mV    809.4mV    928.3mV
1.52ns    899.8mV    858.1mV    950.1mV
2.6ns     900mV      860.1mV    950mV
[Rising Waveform]
R_fixture= 50.0000
V_fixture= 0.0
V_fixture_min= 0.0
V_fixture_max= 0.0
|time   V(typ)   V(min)   V(max)
0s        0V         0V         0V
950ps     -3.2mV     -3.305mV   1.476mV
1.08ns    24.19mV    4.041mV    44.87mV
1.21ns    98.14mV    48.49mV    137.9mV
1.29ns    156.6mV    92.39mV    202.8mV
1.39ns    252.1mV    178mV      299mV
1.6ns     357.3mV    294.9mV    394.6mV
1.73ns    390.4mV    337.2mV    422.6mV
1.94ns    412.4mV    369.7mV    442.1mV
2.6ns     427.1mV    391.1mV    454.5mV
[Falling Waveform]
R_fixture= 50.0000
V_fixture= 0.9000
V_fixture_min= 0.8600
V_fixture_max= 0.9500
|time   V(typ)   V(min)   V(max)
0s        900mV      860mV      950mV
660ps     900.1mV    860mV      950.1mV
1.08ns    880.3mV    843.3mV    928mV
1.16ns    868.2mV    837.6mV    907.1mV
1.29ns    806.5mV    802.1mV    826.4mV
1.34ns    747mV      762.2mV    755mV
1.52ns    583.5mV    633.3mV    575.8mV
1.65ns    511.7mV    547.9mV    510.5mV
1.94ns    463.1mV    476mV      472mV
2.6ns     445.1mV    448.9mV    457.2mV
[Falling Waveform]
R_fixture= 50.0000
V_fixture= 0.0
V_fixture_min= 0.0
V_fixture_max= 0.0
|time   V(typ)   V(min)   V(max)
0s        429.5mV    395.1mV    456.2mV
710ps     427.8mV    395.8mV    446.2mV
740ps     419.2mV    395.6mV    422.7mV
810ps     328mV      373.8mV    286.8mV
870ps     237mV      320.4mV    195.1mV
920ps     162.5mV    243.5mV    133.1mV
1.02ns    76.57mV    114.8mV    63.72mV
1.18ns    24.13mV    37.09mV    19.34mV
1.44ns    1.856mV    3.265mV    1.4mV
2.6ns     166.7uV    227.3uV    140.6uV
